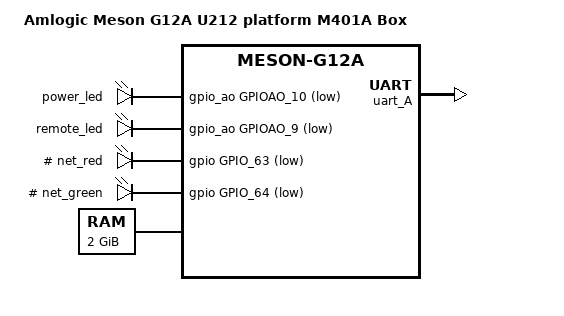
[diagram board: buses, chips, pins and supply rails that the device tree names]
// SPDX-License-Identifier: (GPL-2.0+ OR MIT)
/*
 * Copyright (c) 2018 Amlogic, Inc. All rights reserved.
 * Create by XCray
 */

/dts-v1/;

#include "meson-g12a-u200.dts"

/ {
	compatible = "amlogic,u212\0amlogic,g12a";
	model = "Amlogic Meson G12A U212 platform M401A Box";
	aliases {
	    serial1 = &uart_A;
	};

	leds {
		compatible = "gpio-leds";
		power_led {
			led_name = "power_led";
                        gpios = <&gpio_ao GPIOAO_10 GPIO_ACTIVE_LOW>;
			default-state = "on";
		};
		remote_led {
			led_name = "remote_led";
                        gpios = <&gpio_ao GPIOAO_9 GPIO_ACTIVE_LOW>;
			default-state = "off";
			linux,default-trigger = "rc-feedback";
		};
#		net_red {
#			led_name = "net_red";
#                       gpios = <&gpio GPIO_63 GPIO_ACTIVE_LOW>;
#			default-state = "off";
#			linux,default-trigger = "0.0:00:link";
#		};
#		net_green {
#			led_name = "net_green";
#                       gpios = <&gpio GPIO_64 GPIO_ACTIVE_LOW>;
#			default-state = "off";
#			linux,default-trigger = "0.0:00:link";
#		};
	};
	memory@0 {
		device_type = "memory";
		reg = <0x0 0x0 0x0 0x80000000>;
	};
};
&uart_A {
    status = "okay";
    pinctrl-0 = <&uart_a_pins>, <&uart_a_cts_rts_pins>;
    uart-has-rtscts;
    pinctrl-names = "default";
};
